VERSION 5.7 ;
  NOWIREEXTENSIONATPIN ON ;
  DIVIDERCHAR "/" ;
  BUSBITCHARS "[]" ;
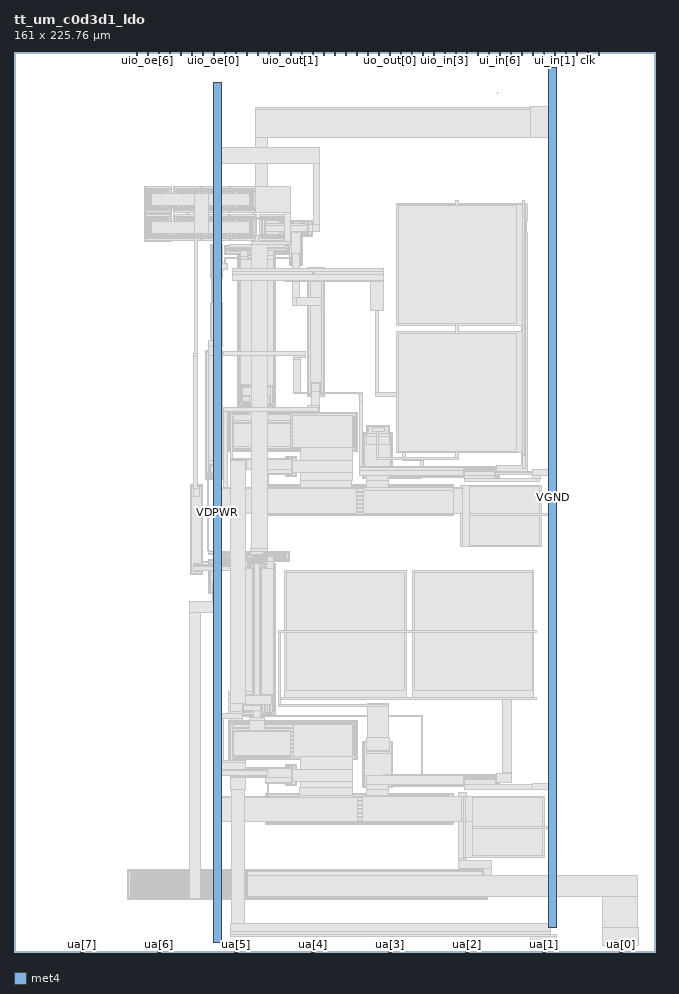
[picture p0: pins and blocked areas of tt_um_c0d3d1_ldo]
MACRO tt_um_c0d3d1_ldo
  CLASS BLOCK ;
  FOREIGN tt_um_c0d3d1_ldo ;
  ORIGIN 0.000 0.000 ;
  SIZE 161.000 BY 225.760 ;
  PIN clk
    DIRECTION INPUT ;
    USE SIGNAL ;
    PORT
      LAYER met4 ;
        RECT 143.830 224.760 144.130 225.760 ;
    END
  END clk
  PIN ena
    DIRECTION INPUT ;
    USE SIGNAL ;
    PORT
      LAYER met4 ;
        RECT 146.590 224.760 146.890 225.760 ;
    END
  END ena
  PIN rst_n
    DIRECTION INPUT ;
    USE SIGNAL ;
    PORT
      LAYER met4 ;
        RECT 141.070 224.760 141.370 225.760 ;
    END
  END rst_n
  PIN ua[0]
    DIRECTION INOUT ;
    USE SIGNAL ;
    ANTENNADIFFAREA 183.919998 ;
    PORT
      LAYER met4 ;
        RECT 151.810 0.000 152.710 1.000 ;
    END
  END ua[0]
  PIN ua[1]
    DIRECTION INOUT ;
    USE SIGNAL ;
    ANTENNAGATEAREA 738.719971 ;
    ANTENNADIFFAREA 1.740000 ;
    PORT
      LAYER met4 ;
        RECT 132.490 0.000 133.390 1.000 ;
    END
  END ua[1]
  PIN ua[2]
    DIRECTION INOUT ;
    USE SIGNAL ;
    PORT
      LAYER met4 ;
        RECT 113.170 0.000 114.070 1.000 ;
    END
  END ua[2]
  PIN ua[3]
    DIRECTION INOUT ;
    USE SIGNAL ;
    PORT
      LAYER met4 ;
        RECT 93.850 0.000 94.750 1.000 ;
    END
  END ua[3]
  PIN ua[4]
    DIRECTION INOUT ;
    USE SIGNAL ;
    PORT
      LAYER met4 ;
        RECT 74.530 0.000 75.430 1.000 ;
    END
  END ua[4]
  PIN ua[5]
    DIRECTION INOUT ;
    USE SIGNAL ;
    PORT
      LAYER met4 ;
        RECT 55.210 0.000 56.110 1.000 ;
    END
  END ua[5]
  PIN ua[6]
    DIRECTION INOUT ;
    USE SIGNAL ;
    PORT
      LAYER met4 ;
        RECT 35.890 0.000 36.790 1.000 ;
    END
  END ua[6]
  PIN ua[7]
    DIRECTION INOUT ;
    USE SIGNAL ;
    PORT
      LAYER met4 ;
        RECT 16.570 0.000 17.470 1.000 ;
    END
  END ua[7]
  PIN ui_in[0]
    DIRECTION INPUT ;
    USE SIGNAL ;
    PORT
      LAYER met4 ;
        RECT 138.310 224.760 138.610 225.760 ;
    END
  END ui_in[0]
  PIN ui_in[1]
    DIRECTION INPUT ;
    USE SIGNAL ;
    PORT
      LAYER met4 ;
        RECT 135.550 224.760 135.850 225.760 ;
    END
  END ui_in[1]
  PIN ui_in[2]
    DIRECTION INPUT ;
    USE SIGNAL ;
    PORT
      LAYER met4 ;
        RECT 132.790 224.760 133.090 225.760 ;
    END
  END ui_in[2]
  PIN ui_in[3]
    DIRECTION INPUT ;
    USE SIGNAL ;
    PORT
      LAYER met4 ;
        RECT 130.030 224.760 130.330 225.760 ;
    END
  END ui_in[3]
  PIN ui_in[4]
    DIRECTION INPUT ;
    USE SIGNAL ;
    PORT
      LAYER met4 ;
        RECT 127.270 224.760 127.570 225.760 ;
    END
  END ui_in[4]
  PIN ui_in[5]
    DIRECTION INPUT ;
    USE SIGNAL ;
    PORT
      LAYER met4 ;
        RECT 124.510 224.760 124.810 225.760 ;
    END
  END ui_in[5]
  PIN ui_in[6]
    DIRECTION INPUT ;
    USE SIGNAL ;
    PORT
      LAYER met4 ;
        RECT 121.750 224.760 122.050 225.760 ;
    END
  END ui_in[6]
  PIN ui_in[7]
    DIRECTION INPUT ;
    USE SIGNAL ;
    PORT
      LAYER met4 ;
        RECT 118.990 224.760 119.290 225.760 ;
    END
  END ui_in[7]
  PIN uio_in[0]
    DIRECTION INPUT ;
    USE SIGNAL ;
    PORT
      LAYER met4 ;
        RECT 116.230 224.760 116.530 225.760 ;
    END
  END uio_in[0]
  PIN uio_in[1]
    DIRECTION INPUT ;
    USE SIGNAL ;
    PORT
      LAYER met4 ;
        RECT 113.470 224.760 113.770 225.760 ;
    END
  END uio_in[1]
  PIN uio_in[2]
    DIRECTION INPUT ;
    USE SIGNAL ;
    PORT
      LAYER met4 ;
        RECT 110.710 224.760 111.010 225.760 ;
    END
  END uio_in[2]
  PIN uio_in[3]
    DIRECTION INPUT ;
    USE SIGNAL ;
    PORT
      LAYER met4 ;
        RECT 107.950 224.760 108.250 225.760 ;
    END
  END uio_in[3]
  PIN uio_in[4]
    DIRECTION INPUT ;
    USE SIGNAL ;
    PORT
      LAYER met4 ;
        RECT 105.190 224.760 105.490 225.760 ;
    END
  END uio_in[4]
  PIN uio_in[5]
    DIRECTION INPUT ;
    USE SIGNAL ;
    PORT
      LAYER met4 ;
        RECT 102.430 224.760 102.730 225.760 ;
    END
  END uio_in[5]
  PIN uio_in[6]
    DIRECTION INPUT ;
    USE SIGNAL ;
    PORT
      LAYER met4 ;
        RECT 99.670 224.760 99.970 225.760 ;
    END
  END uio_in[6]
  PIN uio_in[7]
    DIRECTION INPUT ;
    USE SIGNAL ;
    PORT
      LAYER met4 ;
        RECT 96.910 224.760 97.210 225.760 ;
    END
  END uio_in[7]
  PIN uio_oe[0]
    DIRECTION OUTPUT ;
    USE SIGNAL ;
    PORT
      LAYER met4 ;
        RECT 49.990 224.760 50.290 225.760 ;
    END
  END uio_oe[0]
  PIN uio_oe[1]
    DIRECTION OUTPUT ;
    USE SIGNAL ;
    PORT
      LAYER met4 ;
        RECT 47.230 224.760 47.530 225.760 ;
    END
  END uio_oe[1]
  PIN uio_oe[2]
    DIRECTION OUTPUT ;
    USE SIGNAL ;
    PORT
      LAYER met4 ;
        RECT 44.470 224.760 44.770 225.760 ;
    END
  END uio_oe[2]
  PIN uio_oe[3]
    DIRECTION OUTPUT ;
    USE SIGNAL ;
    PORT
      LAYER met4 ;
        RECT 41.710 224.760 42.010 225.760 ;
    END
  END uio_oe[3]
  PIN uio_oe[4]
    DIRECTION OUTPUT ;
    USE SIGNAL ;
    PORT
      LAYER met4 ;
        RECT 38.950 224.760 39.250 225.760 ;
    END
  END uio_oe[4]
  PIN uio_oe[5]
    DIRECTION OUTPUT ;
    USE SIGNAL ;
    PORT
      LAYER met4 ;
        RECT 36.190 224.760 36.490 225.760 ;
    END
  END uio_oe[5]
  PIN uio_oe[6]
    DIRECTION OUTPUT ;
    USE SIGNAL ;
    PORT
      LAYER met4 ;
        RECT 33.430 224.760 33.730 225.760 ;
    END
  END uio_oe[6]
  PIN uio_oe[7]
    DIRECTION OUTPUT ;
    USE SIGNAL ;
    PORT
      LAYER met4 ;
        RECT 30.670 224.760 30.970 225.760 ;
    END
  END uio_oe[7]
  PIN uio_out[0]
    DIRECTION OUTPUT ;
    USE SIGNAL ;
    PORT
      LAYER met4 ;
        RECT 72.070 224.760 72.370 225.760 ;
    END
  END uio_out[0]
  PIN uio_out[1]
    DIRECTION OUTPUT ;
    USE SIGNAL ;
    PORT
      LAYER met4 ;
        RECT 69.310 224.760 69.610 225.760 ;
    END
  END uio_out[1]
  PIN uio_out[2]
    DIRECTION OUTPUT ;
    USE SIGNAL ;
    PORT
      LAYER met4 ;
        RECT 66.550 224.760 66.850 225.760 ;
    END
  END uio_out[2]
  PIN uio_out[3]
    DIRECTION OUTPUT ;
    USE SIGNAL ;
    PORT
      LAYER met4 ;
        RECT 63.790 224.760 64.090 225.760 ;
    END
  END uio_out[3]
  PIN uio_out[4]
    DIRECTION OUTPUT ;
    USE SIGNAL ;
    PORT
      LAYER met4 ;
        RECT 61.030 224.760 61.330 225.760 ;
    END
  END uio_out[4]
  PIN uio_out[5]
    DIRECTION OUTPUT ;
    USE SIGNAL ;
    PORT
      LAYER met4 ;
        RECT 58.270 224.760 58.570 225.760 ;
    END
  END uio_out[5]
  PIN uio_out[6]
    DIRECTION OUTPUT ;
    USE SIGNAL ;
    PORT
      LAYER met4 ;
        RECT 55.510 224.760 55.810 225.760 ;
    END
  END uio_out[6]
  PIN uio_out[7]
    DIRECTION OUTPUT ;
    USE SIGNAL ;
    PORT
      LAYER met4 ;
        RECT 52.750 224.760 53.050 225.760 ;
    END
  END uio_out[7]
  PIN uo_out[0]
    DIRECTION OUTPUT ;
    USE SIGNAL ;
    PORT
      LAYER met4 ;
        RECT 94.150 224.760 94.450 225.760 ;
    END
  END uo_out[0]
  PIN uo_out[1]
    DIRECTION OUTPUT ;
    USE SIGNAL ;
    PORT
      LAYER met4 ;
        RECT 91.390 224.760 91.690 225.760 ;
    END
  END uo_out[1]
  PIN uo_out[2]
    DIRECTION OUTPUT ;
    USE SIGNAL ;
    PORT
      LAYER met4 ;
        RECT 88.630 224.760 88.930 225.760 ;
    END
  END uo_out[2]
  PIN uo_out[3]
    DIRECTION OUTPUT ;
    USE SIGNAL ;
    PORT
      LAYER met4 ;
        RECT 85.870 224.760 86.170 225.760 ;
    END
  END uo_out[3]
  PIN uo_out[4]
    DIRECTION OUTPUT ;
    USE SIGNAL ;
    PORT
      LAYER met4 ;
        RECT 83.110 224.760 83.410 225.760 ;
    END
  END uo_out[4]
  PIN uo_out[5]
    DIRECTION OUTPUT ;
    USE SIGNAL ;
    PORT
      LAYER met4 ;
        RECT 80.350 224.760 80.650 225.760 ;
    END
  END uo_out[5]
  PIN uo_out[6]
    DIRECTION OUTPUT ;
    USE SIGNAL ;
    PORT
      LAYER met4 ;
        RECT 77.590 224.760 77.890 225.760 ;
    END
  END uo_out[6]
  PIN uo_out[7]
    DIRECTION OUTPUT ;
    USE SIGNAL ;
    PORT
      LAYER met4 ;
        RECT 74.830 224.760 75.130 225.760 ;
    END
  END uo_out[7]
  PIN VDPWR
    DIRECTION INOUT ;
    USE POWER ;
    PORT
      LAYER met4 ;
        RECT 50.120 2.420 52.120 218.180 ;
    END
  END VDPWR
  PIN VGND
    DIRECTION INOUT ;
    USE GROUND ;
    PORT
      LAYER met4 ;
        RECT 134.120 6.130 136.120 221.890 ;
    END
  END VGND
  OBS
      LAYER pwell ;
        RECT 121.160 215.360 121.200 215.600 ;
        RECT 135.160 215.360 135.200 215.600 ;
        RECT 32.735 191.265 39.435 192.030 ;
        RECT 32.735 186.095 33.500 191.265 ;
        RECT 38.670 186.095 39.435 191.265 ;
        RECT 32.735 185.330 39.435 186.095 ;
        RECT 40.125 191.325 46.825 192.090 ;
        RECT 40.125 186.155 40.890 191.325 ;
        RECT 46.060 186.155 46.825 191.325 ;
        RECT 40.125 185.390 46.825 186.155 ;
        RECT 47.125 191.325 53.825 192.090 ;
        RECT 47.125 186.155 47.890 191.325 ;
        RECT 53.060 186.155 53.825 191.325 ;
        RECT 47.125 185.390 53.825 186.155 ;
        RECT 54.125 191.325 60.825 192.090 ;
        RECT 54.125 186.155 54.890 191.325 ;
        RECT 60.060 186.155 60.825 191.325 ;
        RECT 54.125 185.390 60.825 186.155 ;
        RECT 32.735 184.265 39.435 185.030 ;
        RECT 32.735 179.095 33.500 184.265 ;
        RECT 38.670 179.095 39.435 184.265 ;
        RECT 32.735 178.330 39.435 179.095 ;
        RECT 40.125 184.325 46.825 185.090 ;
        RECT 40.125 179.155 40.890 184.325 ;
        RECT 46.060 179.155 46.825 184.325 ;
        RECT 40.125 178.390 46.825 179.155 ;
        RECT 47.125 184.325 53.825 185.090 ;
        RECT 47.125 179.155 47.890 184.325 ;
        RECT 53.060 179.155 53.825 184.325 ;
        RECT 47.125 178.390 53.825 179.155 ;
        RECT 54.125 184.325 60.825 185.090 ;
        RECT 54.125 179.155 54.890 184.325 ;
        RECT 60.060 179.155 60.825 184.325 ;
        RECT 54.125 178.390 60.825 179.155 ;
        RECT 61.490 184.335 68.190 185.100 ;
        RECT 61.490 179.165 62.255 184.335 ;
        RECT 67.425 179.165 68.190 184.335 ;
        RECT 61.490 178.400 68.190 179.165 ;
        RECT 49.340 169.310 52.410 177.580 ;
        RECT 52.920 174.970 61.020 177.290 ;
        RECT 61.060 175.010 69.160 177.330 ;
      LAYER nwell ;
        RECT 56.170 174.910 60.440 174.940 ;
        RECT 56.170 174.870 61.720 174.910 ;
      LAYER pwell ;
        RECT 49.280 152.000 52.350 162.940 ;
      LAYER nwell ;
        RECT 48.030 118.640 52.300 150.830 ;
        RECT 56.170 136.750 65.695 174.870 ;
      LAYER pwell ;
        RECT 69.230 172.120 72.300 183.540 ;
      LAYER nwell ;
        RECT 72.615 179.585 74.935 183.575 ;
        RECT 73.600 139.430 77.870 171.620 ;
        RECT 60.170 136.690 65.695 136.750 ;
        RECT 61.425 136.680 65.695 136.690 ;
        RECT 53.880 125.650 86.070 135.400 ;
        RECT 68.170 119.160 70.850 124.350 ;
      LAYER pwell ;
        RECT 87.520 118.670 94.910 130.220 ;
        RECT 101.770 118.920 121.870 121.890 ;
        RECT 44.270 94.580 47.340 117.150 ;
      LAYER nwell ;
        RECT 63.010 109.450 110.200 117.180 ;
      LAYER pwell ;
        RECT 48.900 98.450 51.970 98.470 ;
        RECT 48.860 90.000 51.970 98.450 ;
        RECT 52.650 98.060 60.750 100.380 ;
        RECT 61.000 98.080 69.100 100.400 ;
      LAYER nwell ;
        RECT 56.190 97.520 60.460 97.530 ;
        RECT 56.190 97.460 61.640 97.520 ;
      LAYER pwell ;
        RECT 48.860 89.980 51.930 90.000 ;
      LAYER nwell ;
        RECT 56.190 59.340 65.715 97.460 ;
        RECT 59.160 59.290 65.715 59.340 ;
        RECT 61.445 59.270 65.715 59.290 ;
        RECT 59.160 57.990 63.230 58.000 ;
        RECT 53.900 48.240 86.090 57.990 ;
        RECT 68.190 41.750 70.870 46.940 ;
      LAYER pwell ;
        RECT 87.540 41.260 94.930 52.810 ;
        RECT 101.790 41.510 121.890 44.480 ;
      LAYER nwell ;
        RECT 63.030 32.040 110.220 39.770 ;
        RECT 28.485 13.205 118.675 20.635 ;
      LAYER li1 ;
        RECT 60.600 191.960 63.530 191.970 ;
        RECT 32.865 191.405 39.305 191.900 ;
        RECT 32.865 185.955 33.360 191.405 ;
        RECT 33.680 190.725 38.490 191.085 ;
        RECT 33.680 186.635 34.040 190.725 ;
        RECT 34.350 186.945 37.820 190.415 ;
        RECT 38.130 186.900 38.490 190.725 ;
        RECT 38.810 186.900 39.305 191.405 ;
        RECT 38.130 186.890 39.305 186.900 ;
        RECT 40.255 191.465 46.695 191.960 ;
        RECT 40.255 191.065 40.750 191.465 ;
        RECT 41.070 191.065 45.880 191.145 ;
        RECT 46.200 191.065 46.695 191.465 ;
        RECT 47.255 191.465 53.695 191.960 ;
        RECT 47.255 191.065 47.750 191.465 ;
        RECT 48.070 191.065 52.880 191.145 ;
        RECT 53.200 191.065 53.695 191.465 ;
        RECT 54.255 191.465 63.530 191.960 ;
        RECT 54.255 191.065 54.750 191.465 ;
        RECT 55.070 191.065 59.880 191.145 ;
        RECT 60.200 191.065 63.530 191.465 ;
        RECT 40.255 190.785 63.530 191.065 ;
        RECT 40.255 186.890 40.750 190.785 ;
        RECT 38.130 186.695 40.750 186.890 ;
        RECT 41.070 186.695 41.430 190.785 ;
        RECT 41.740 187.005 45.210 190.475 ;
        RECT 45.520 186.695 45.880 190.785 ;
        RECT 46.200 186.695 46.695 190.785 ;
        RECT 47.255 186.695 47.750 190.785 ;
        RECT 48.070 186.695 48.430 190.785 ;
        RECT 48.740 187.005 52.210 190.475 ;
        RECT 52.520 186.695 52.880 190.785 ;
        RECT 53.200 186.695 53.695 190.785 ;
        RECT 54.255 186.695 54.750 190.785 ;
        RECT 55.070 186.695 55.430 190.785 ;
        RECT 55.740 187.005 59.210 190.475 ;
        RECT 59.520 186.695 59.880 190.785 ;
        RECT 60.200 186.695 63.530 190.785 ;
        RECT 38.130 186.635 63.530 186.695 ;
        RECT 33.680 186.450 63.530 186.635 ;
        RECT 33.680 186.430 39.305 186.450 ;
        RECT 33.680 186.275 38.490 186.430 ;
        RECT 38.810 185.955 39.305 186.430 ;
        RECT 32.865 185.460 39.305 185.955 ;
        RECT 40.255 186.335 63.530 186.450 ;
        RECT 40.255 186.015 40.750 186.335 ;
        RECT 46.200 186.015 46.695 186.335 ;
        RECT 40.255 185.520 46.695 186.015 ;
        RECT 47.255 186.015 47.750 186.335 ;
        RECT 53.200 186.015 53.695 186.335 ;
        RECT 47.255 185.520 53.695 186.015 ;
        RECT 54.255 186.015 54.750 186.335 ;
        RECT 60.200 186.015 63.530 186.335 ;
        RECT 54.255 185.550 63.530 186.015 ;
        RECT 54.255 185.520 60.695 185.550 ;
        RECT 33.440 184.900 33.985 185.460 ;
        RECT 43.345 184.960 43.840 185.520 ;
        RECT 50.345 184.960 50.830 185.520 ;
        RECT 59.920 184.960 60.355 185.520 ;
        RECT 32.865 184.405 39.305 184.900 ;
        RECT 32.865 178.955 33.360 184.405 ;
        RECT 33.680 183.725 38.490 184.085 ;
        RECT 33.680 179.635 34.040 183.725 ;
        RECT 34.350 179.945 37.820 183.415 ;
        RECT 38.130 179.750 38.490 183.725 ;
        RECT 38.810 179.750 39.305 184.405 ;
        RECT 38.130 179.710 39.305 179.750 ;
        RECT 40.255 184.465 46.695 184.960 ;
        RECT 40.255 184.115 40.750 184.465 ;
        RECT 41.070 184.120 45.880 184.145 ;
        RECT 46.200 184.120 46.695 184.465 ;
        RECT 47.255 184.465 53.695 184.960 ;
        RECT 47.255 184.120 47.750 184.465 ;
        RECT 48.070 184.120 52.880 184.145 ;
        RECT 53.200 184.120 53.695 184.465 ;
        RECT 54.255 184.465 60.695 184.960 ;
        RECT 54.255 184.120 54.750 184.465 ;
        RECT 55.070 184.120 59.880 184.145 ;
        RECT 60.200 184.120 60.695 184.465 ;
        RECT 61.620 184.475 68.060 184.970 ;
        RECT 61.620 184.120 62.115 184.475 ;
        RECT 62.435 184.120 67.245 184.155 ;
        RECT 41.070 184.115 67.245 184.120 ;
        RECT 40.255 183.845 67.245 184.115 ;
        RECT 40.255 183.275 40.760 183.845 ;
        RECT 41.070 183.840 67.245 183.845 ;
        RECT 41.070 183.785 45.880 183.840 ;
        RECT 40.255 180.205 40.750 183.275 ;
        RECT 40.255 179.770 40.760 180.205 ;
        RECT 41.070 179.770 41.430 183.785 ;
        RECT 41.740 180.005 45.210 183.475 ;
        RECT 45.520 179.770 45.880 183.785 ;
        RECT 46.200 179.770 46.695 183.840 ;
        RECT 47.255 179.770 47.750 183.840 ;
        RECT 48.070 183.785 52.880 183.840 ;
        RECT 48.070 179.770 48.430 183.785 ;
        RECT 48.740 180.005 52.210 183.475 ;
        RECT 52.520 179.770 52.880 183.785 ;
        RECT 53.200 179.770 53.695 183.840 ;
        RECT 54.255 179.770 54.750 183.840 ;
        RECT 55.070 183.785 59.880 183.840 ;
        RECT 55.070 179.770 55.430 183.785 ;
        RECT 55.740 180.005 59.210 183.475 ;
        RECT 59.520 179.770 59.880 183.785 ;
        RECT 60.200 179.770 60.695 183.840 ;
        RECT 61.620 179.980 62.115 183.840 ;
        RECT 62.435 183.795 67.245 183.840 ;
        RECT 62.435 179.980 62.795 183.795 ;
        RECT 63.105 180.015 66.575 183.485 ;
        RECT 66.885 183.370 67.245 183.795 ;
        RECT 67.565 183.370 68.060 184.475 ;
        RECT 66.885 183.360 70.220 183.370 ;
        RECT 66.885 183.190 72.120 183.360 ;
        RECT 66.885 183.020 70.220 183.190 ;
        RECT 61.620 179.770 62.795 179.980 ;
        RECT 40.255 179.710 62.795 179.770 ;
        RECT 38.130 179.705 62.795 179.710 ;
        RECT 66.885 179.705 67.245 183.020 ;
        RECT 38.130 179.635 67.245 179.705 ;
        RECT 33.680 179.410 67.245 179.635 ;
        RECT 33.680 179.320 40.750 179.410 ;
        RECT 41.070 179.335 45.880 179.410 ;
        RECT 33.680 179.275 38.490 179.320 ;
        RECT 38.810 179.270 40.750 179.320 ;
        RECT 38.810 179.030 39.305 179.270 ;
        RECT 40.255 179.030 40.750 179.270 ;
        RECT 38.810 179.015 40.750 179.030 ;
        RECT 46.200 179.015 46.695 179.410 ;
        RECT 38.810 178.955 46.695 179.015 ;
        RECT 32.865 178.570 46.695 178.955 ;
        RECT 32.865 178.460 39.305 178.570 ;
        RECT 40.255 178.520 46.695 178.570 ;
        RECT 47.255 179.015 47.750 179.410 ;
        RECT 48.070 179.335 52.880 179.410 ;
        RECT 53.200 179.015 53.695 179.410 ;
        RECT 47.255 178.520 53.695 179.015 ;
        RECT 54.255 179.015 54.750 179.410 ;
        RECT 55.070 179.335 59.880 179.410 ;
        RECT 60.200 179.025 62.115 179.410 ;
        RECT 62.435 179.345 67.245 179.410 ;
        RECT 67.565 179.025 68.060 183.020 ;
        RECT 60.200 179.015 68.060 179.025 ;
        RECT 54.255 178.530 68.060 179.015 ;
        RECT 54.255 178.520 61.830 178.530 ;
        RECT 45.160 177.950 45.980 178.520 ;
        RECT 49.960 177.400 51.800 178.520 ;
        RECT 60.470 178.460 61.830 178.520 ;
        RECT 60.470 178.440 61.470 178.460 ;
        RECT 49.520 177.230 52.230 177.400 ;
        RECT 49.520 170.070 49.690 177.230 ;
        RECT 50.170 174.590 51.580 176.750 ;
        RECT 50.170 170.140 51.580 172.300 ;
        RECT 49.450 169.660 49.790 170.070 ;
        RECT 52.060 169.660 52.230 177.230 ;
        RECT 53.100 176.940 60.840 177.110 ;
        RECT 53.100 175.320 53.270 176.940 ;
        RECT 55.470 176.540 58.440 176.940 ;
        RECT 53.950 176.370 59.990 176.540 ;
        RECT 53.610 175.950 53.780 176.310 ;
        RECT 60.160 175.950 60.330 176.310 ;
        RECT 53.950 175.720 59.990 175.890 ;
        RECT 60.670 175.320 60.840 176.940 ;
        RECT 53.100 175.150 60.840 175.320 ;
        RECT 61.240 176.980 68.980 177.150 ;
        RECT 61.240 175.360 61.410 176.980 ;
        RECT 63.580 176.580 66.550 176.980 ;
        RECT 62.090 176.410 68.130 176.580 ;
        RECT 61.750 175.990 61.920 176.350 ;
        RECT 68.300 175.990 68.470 176.350 ;
        RECT 62.090 175.760 68.130 175.930 ;
        RECT 68.810 175.360 68.980 176.980 ;
        RECT 61.240 175.190 68.980 175.360 ;
        RECT 49.450 169.490 52.230 169.660 ;
        RECT 56.350 174.590 60.260 174.760 ;
        RECT 49.450 162.760 49.790 169.490 ;
        RECT 49.450 162.600 52.170 162.760 ;
        RECT 49.460 162.590 52.170 162.600 ;
        RECT 49.460 152.350 49.630 162.590 ;
        RECT 50.110 159.950 51.520 162.110 ;
        RECT 50.110 152.830 51.520 154.990 ;
        RECT 52.000 152.350 52.170 162.590 ;
        RECT 49.460 152.180 52.170 152.350 ;
        RECT 48.210 150.480 52.120 150.650 ;
        RECT 48.210 118.990 48.380 150.480 ;
        RECT 49.010 149.970 49.370 150.140 ;
        RECT 49.660 149.970 50.020 150.140 ;
        RECT 50.310 149.970 50.670 150.140 ;
        RECT 50.960 149.970 51.320 150.140 ;
        RECT 48.780 119.715 48.950 149.755 ;
        RECT 49.430 119.715 49.600 149.755 ;
        RECT 50.080 119.715 50.250 149.755 ;
        RECT 50.730 119.715 50.900 149.755 ;
        RECT 51.380 119.715 51.550 149.755 ;
        RECT 49.010 119.330 49.370 119.500 ;
        RECT 49.660 119.330 50.020 119.500 ;
        RECT 50.310 119.330 50.670 119.500 ;
        RECT 50.960 119.330 51.320 119.500 ;
        RECT 50.580 118.990 51.580 119.010 ;
        RECT 51.950 118.990 52.120 150.480 ;
        RECT 56.350 137.100 56.520 174.590 ;
        RECT 57.150 174.080 57.510 174.250 ;
        RECT 57.800 174.080 58.160 174.250 ;
        RECT 58.450 174.080 58.810 174.250 ;
        RECT 59.100 174.080 59.460 174.250 ;
        RECT 56.920 137.825 57.090 173.865 ;
        RECT 57.570 137.825 57.740 173.865 ;
        RECT 58.220 137.825 58.390 173.865 ;
        RECT 58.870 137.825 59.040 173.865 ;
        RECT 59.520 137.825 59.690 173.865 ;
        RECT 60.090 138.280 60.260 174.590 ;
        RECT 61.605 174.520 65.515 174.690 ;
        RECT 61.605 138.280 61.775 174.520 ;
        RECT 62.405 174.010 62.765 174.180 ;
        RECT 63.055 174.010 63.415 174.180 ;
        RECT 63.705 174.010 64.065 174.180 ;
        RECT 64.355 174.010 64.715 174.180 ;
        RECT 57.365 137.610 59.185 137.640 ;
        RECT 57.150 137.440 59.460 137.610 ;
        RECT 60.090 137.490 61.780 138.280 ;
        RECT 62.175 137.755 62.345 173.795 ;
        RECT 62.825 137.755 62.995 173.795 ;
        RECT 63.475 137.755 63.645 173.795 ;
        RECT 64.125 137.755 64.295 173.795 ;
        RECT 64.775 137.755 64.945 173.795 ;
        RECT 60.090 137.100 60.260 137.490 ;
        RECT 56.350 136.930 60.260 137.100 ;
        RECT 61.605 137.030 61.775 137.490 ;
        RECT 62.405 137.370 62.765 137.540 ;
        RECT 63.055 137.370 63.415 137.540 ;
        RECT 63.705 137.370 64.065 137.540 ;
        RECT 64.355 137.370 64.715 137.540 ;
        RECT 65.345 137.030 65.515 174.520 ;
        RECT 69.410 172.470 69.580 183.020 ;
        RECT 70.060 180.550 71.470 182.710 ;
        RECT 70.060 172.950 71.470 175.110 ;
        RECT 71.950 172.470 72.120 183.190 ;
        RECT 72.795 183.225 74.755 183.395 ;
        RECT 72.795 179.935 72.965 183.225 ;
        RECT 73.595 182.715 73.955 182.885 ;
        RECT 73.365 180.660 73.535 182.500 ;
        RECT 74.015 182.260 74.185 182.500 ;
        RECT 74.585 182.260 74.755 183.225 ;
        RECT 74.015 180.840 74.755 182.260 ;
        RECT 74.015 180.660 74.185 180.840 ;
        RECT 73.595 180.275 73.955 180.445 ;
        RECT 74.585 179.935 74.755 180.840 ;
        RECT 72.795 179.765 74.755 179.935 ;
        RECT 69.410 172.300 72.120 172.470 ;
        RECT 73.780 171.270 77.690 171.440 ;
        RECT 73.780 139.780 73.950 171.270 ;
        RECT 74.580 170.760 74.940 170.930 ;
        RECT 75.230 170.760 75.590 170.930 ;
        RECT 75.880 170.760 76.240 170.930 ;
        RECT 76.530 170.760 76.890 170.930 ;
        RECT 74.350 140.505 74.520 170.545 ;
        RECT 75.000 140.505 75.170 170.545 ;
        RECT 75.650 140.505 75.820 170.545 ;
        RECT 76.300 140.505 76.470 170.545 ;
        RECT 76.950 140.505 77.120 170.545 ;
        RECT 74.580 140.120 74.940 140.290 ;
        RECT 75.230 140.120 75.590 140.290 ;
        RECT 75.880 140.120 76.240 140.290 ;
        RECT 76.530 140.120 76.890 140.290 ;
        RECT 77.520 139.810 77.690 171.270 ;
        RECT 77.220 139.780 77.700 139.810 ;
        RECT 73.780 139.610 77.700 139.780 ;
        RECT 77.220 139.270 77.700 139.610 ;
        RECT 61.605 136.860 65.515 137.030 ;
        RECT 54.060 135.050 85.890 135.220 ;
        RECT 54.060 126.000 54.230 135.050 ;
        RECT 54.955 134.480 84.995 134.650 ;
        RECT 54.570 133.700 54.740 134.420 ;
        RECT 85.210 133.700 85.380 134.420 ;
        RECT 54.955 133.470 84.995 133.640 ;
        RECT 54.570 132.690 54.740 133.410 ;
        RECT 85.210 132.690 85.380 133.410 ;
        RECT 54.955 132.460 84.995 132.630 ;
        RECT 54.570 131.680 54.740 132.400 ;
        RECT 85.210 131.680 85.380 132.400 ;
        RECT 54.955 131.450 84.995 131.620 ;
        RECT 54.570 130.670 54.740 131.390 ;
        RECT 85.210 130.670 85.380 131.390 ;
        RECT 54.955 130.440 84.995 130.610 ;
        RECT 54.570 129.660 54.740 130.380 ;
        RECT 85.210 129.660 85.380 130.380 ;
        RECT 54.955 129.430 84.995 129.600 ;
        RECT 54.570 128.650 54.740 129.370 ;
        RECT 85.210 128.650 85.380 129.370 ;
        RECT 54.955 128.420 84.995 128.590 ;
        RECT 54.570 127.640 54.740 128.360 ;
        RECT 85.210 127.640 85.380 128.360 ;
        RECT 54.955 127.410 84.995 127.580 ;
        RECT 54.570 126.630 54.740 127.350 ;
        RECT 85.210 126.630 85.380 127.350 ;
        RECT 54.955 126.400 84.995 126.570 ;
        RECT 85.720 126.000 85.890 135.050 ;
        RECT 54.060 125.830 85.890 126.000 ;
        RECT 87.700 129.870 94.730 130.040 ;
        RECT 71.810 125.580 84.800 125.830 ;
        RECT 68.350 124.000 70.670 124.170 ;
        RECT 68.350 119.510 68.520 124.000 ;
        RECT 69.150 123.490 69.870 123.660 ;
        RECT 68.920 120.235 69.090 123.275 ;
        RECT 69.930 123.240 70.100 123.275 ;
        RECT 70.500 123.240 70.670 124.000 ;
        RECT 69.930 120.410 70.670 123.240 ;
        RECT 69.930 120.235 70.100 120.410 ;
        RECT 69.150 119.850 69.870 120.020 ;
        RECT 70.500 119.510 70.670 120.410 ;
        RECT 68.350 119.340 70.670 119.510 ;
        RECT 48.210 118.820 52.120 118.990 ;
        RECT 87.700 119.020 87.870 129.870 ;
        RECT 88.350 127.230 94.080 129.390 ;
        RECT 88.350 119.500 94.080 121.660 ;
        RECT 94.560 119.260 94.730 129.870 ;
        RECT 101.950 121.540 121.690 121.710 ;
        RECT 101.950 119.270 102.120 121.540 ;
        RECT 102.800 120.970 120.840 121.140 ;
        RECT 102.460 120.550 102.630 120.910 ;
        RECT 121.010 120.550 121.180 120.910 ;
        RECT 102.800 120.320 120.840 120.490 ;
        RECT 102.460 119.900 102.630 120.260 ;
        RECT 121.010 119.900 121.180 120.260 ;
        RECT 102.800 119.670 120.840 119.840 ;
        RECT 113.100 119.270 120.580 119.340 ;
        RECT 121.520 119.270 121.690 121.540 ;
        RECT 101.950 119.260 121.690 119.270 ;
        RECT 94.540 119.100 121.690 119.260 ;
        RECT 94.540 119.020 102.250 119.100 ;
        RECT 87.700 118.870 102.250 119.020 ;
        RECT 87.700 118.850 94.730 118.870 ;
        RECT 113.100 118.850 120.580 119.100 ;
        RECT 50.580 118.390 51.580 118.820 ;
        RECT 71.840 117.000 84.680 117.280 ;
        RECT 44.450 116.800 47.160 116.970 ;
        RECT 44.450 94.930 44.620 116.800 ;
        RECT 45.200 116.320 46.500 116.800 ;
        RECT 45.100 114.160 46.510 116.320 ;
        RECT 46.990 97.850 47.160 116.800 ;
        RECT 63.190 116.830 110.020 117.000 ;
        RECT 63.190 109.800 63.360 116.830 ;
        RECT 64.085 116.260 109.125 116.430 ;
        RECT 63.700 115.480 63.870 116.200 ;
        RECT 109.340 115.480 109.510 116.200 ;
        RECT 64.085 115.250 109.125 115.420 ;
        RECT 63.700 114.470 63.870 115.190 ;
        RECT 109.340 114.470 109.510 115.190 ;
        RECT 64.085 114.240 109.125 114.410 ;
        RECT 63.700 113.460 63.870 114.180 ;
        RECT 109.340 113.460 109.510 114.180 ;
        RECT 64.085 113.230 109.125 113.400 ;
        RECT 63.700 112.450 63.870 113.170 ;
        RECT 109.340 112.450 109.510 113.170 ;
        RECT 64.085 112.220 109.125 112.390 ;
        RECT 63.700 111.440 63.870 112.160 ;
        RECT 109.340 111.440 109.510 112.160 ;
        RECT 64.085 111.210 109.125 111.380 ;
        RECT 63.700 110.430 63.870 111.150 ;
        RECT 109.340 110.430 109.510 111.150 ;
        RECT 64.085 110.200 109.125 110.370 ;
        RECT 109.850 109.800 110.020 116.830 ;
        RECT 63.190 109.630 110.020 109.800 ;
        RECT 52.830 100.030 60.570 100.200 ;
        RECT 52.830 98.410 53.000 100.030 ;
        RECT 56.290 99.630 56.730 100.030 ;
        RECT 53.680 99.460 59.720 99.630 ;
        RECT 56.290 99.430 56.730 99.460 ;
        RECT 53.340 99.040 53.510 99.400 ;
        RECT 59.890 99.040 60.060 99.400 ;
        RECT 53.680 98.810 59.720 98.980 ;
        RECT 60.400 98.410 60.570 100.030 ;
        RECT 49.080 98.120 51.790 98.290 ;
        RECT 52.830 98.240 60.570 98.410 ;
        RECT 61.180 100.050 68.920 100.220 ;
        RECT 61.180 98.430 61.350 100.050 ;
        RECT 64.540 99.650 64.980 100.050 ;
        RECT 62.030 99.480 68.070 99.650 ;
        RECT 61.690 99.060 61.860 99.420 ;
        RECT 68.240 99.060 68.410 99.420 ;
        RECT 62.030 98.830 68.070 99.000 ;
        RECT 68.750 98.430 68.920 100.050 ;
        RECT 61.180 98.260 68.920 98.430 ;
        RECT 49.080 97.850 49.250 98.120 ;
        RECT 46.990 97.600 49.280 97.850 ;
        RECT 45.100 95.410 46.510 97.570 ;
        RECT 46.990 94.930 47.160 97.600 ;
        RECT 44.450 94.760 47.160 94.930 ;
        RECT 49.080 90.350 49.250 97.600 ;
        RECT 49.730 95.480 51.140 97.640 ;
        RECT 49.730 90.830 51.140 92.990 ;
        RECT 51.620 90.350 51.790 98.120 ;
        RECT 49.080 90.180 51.790 90.350 ;
        RECT 56.370 97.180 60.280 97.350 ;
        RECT 56.370 59.690 56.540 97.180 ;
        RECT 57.170 96.670 57.530 96.840 ;
        RECT 57.820 96.670 58.180 96.840 ;
        RECT 58.470 96.670 58.830 96.840 ;
        RECT 59.120 96.670 59.480 96.840 ;
        RECT 56.940 60.415 57.110 96.455 ;
        RECT 57.590 60.415 57.760 96.455 ;
        RECT 58.240 60.415 58.410 96.455 ;
        RECT 58.890 60.415 59.060 96.455 ;
        RECT 59.540 60.415 59.710 96.455 ;
        RECT 60.110 61.440 60.280 97.180 ;
        RECT 61.625 97.110 65.535 97.280 ;
        RECT 61.625 61.440 61.795 97.110 ;
        RECT 62.425 96.600 62.785 96.770 ;
        RECT 63.075 96.600 63.435 96.770 ;
        RECT 63.725 96.600 64.085 96.770 ;
        RECT 64.375 96.600 64.735 96.770 ;
        RECT 60.110 60.450 61.795 61.440 ;
        RECT 57.385 60.200 59.205 60.230 ;
        RECT 57.170 60.030 59.480 60.200 ;
        RECT 60.110 59.690 60.280 60.450 ;
        RECT 56.370 59.520 60.280 59.690 ;
        RECT 61.625 59.620 61.795 60.450 ;
        RECT 62.195 60.345 62.365 96.385 ;
        RECT 62.845 60.345 63.015 96.385 ;
        RECT 63.495 60.345 63.665 96.385 ;
        RECT 64.145 60.345 64.315 96.385 ;
        RECT 64.795 60.345 64.965 96.385 ;
        RECT 62.425 59.960 62.785 60.130 ;
        RECT 63.075 59.960 63.435 60.130 ;
        RECT 63.725 59.960 64.085 60.130 ;
        RECT 64.375 59.960 64.735 60.130 ;
        RECT 65.365 59.620 65.535 97.110 ;
        RECT 61.625 59.450 65.535 59.620 ;
        RECT 54.080 57.640 85.910 57.810 ;
        RECT 54.080 48.590 54.250 57.640 ;
        RECT 54.975 57.070 85.015 57.240 ;
        RECT 54.590 56.290 54.760 57.010 ;
        RECT 85.230 56.290 85.400 57.010 ;
        RECT 54.975 56.060 85.015 56.230 ;
        RECT 54.590 55.280 54.760 56.000 ;
        RECT 85.230 55.280 85.400 56.000 ;
        RECT 54.975 55.050 85.015 55.220 ;
        RECT 54.590 54.270 54.760 54.990 ;
        RECT 85.230 54.270 85.400 54.990 ;
        RECT 54.975 54.040 85.015 54.210 ;
        RECT 54.590 53.260 54.760 53.980 ;
        RECT 85.230 53.260 85.400 53.980 ;
        RECT 54.975 53.030 85.015 53.200 ;
        RECT 54.590 52.250 54.760 52.970 ;
        RECT 85.230 52.250 85.400 52.970 ;
        RECT 54.975 52.020 85.015 52.190 ;
        RECT 54.590 51.240 54.760 51.960 ;
        RECT 85.230 51.240 85.400 51.960 ;
        RECT 54.975 51.010 85.015 51.180 ;
        RECT 54.590 50.230 54.760 50.950 ;
        RECT 85.230 50.230 85.400 50.950 ;
        RECT 54.975 50.000 85.015 50.170 ;
        RECT 54.590 49.220 54.760 49.940 ;
        RECT 85.230 49.220 85.400 49.940 ;
        RECT 54.975 48.990 85.015 49.160 ;
        RECT 85.740 48.590 85.910 57.640 ;
        RECT 54.080 48.420 85.910 48.590 ;
        RECT 87.720 52.460 94.750 52.630 ;
        RECT 71.810 48.010 84.810 48.420 ;
        RECT 68.370 46.590 70.690 46.760 ;
        RECT 68.370 42.100 68.540 46.590 ;
        RECT 69.170 46.080 69.890 46.250 ;
        RECT 68.940 42.825 69.110 45.865 ;
        RECT 69.950 45.830 70.120 45.865 ;
        RECT 70.520 45.830 70.690 46.590 ;
        RECT 69.950 43.000 70.690 45.830 ;
        RECT 69.950 42.825 70.120 43.000 ;
        RECT 69.170 42.440 69.890 42.610 ;
        RECT 70.520 42.100 70.690 43.000 ;
        RECT 68.370 41.930 70.690 42.100 ;
        RECT 87.720 41.610 87.890 52.460 ;
        RECT 88.370 49.820 94.100 51.980 ;
        RECT 88.370 42.090 94.100 44.250 ;
        RECT 94.580 41.860 94.750 52.460 ;
        RECT 101.970 44.130 121.710 44.300 ;
        RECT 101.970 41.860 102.140 44.130 ;
        RECT 102.820 43.560 120.860 43.730 ;
        RECT 102.480 43.140 102.650 43.500 ;
        RECT 121.030 43.140 121.200 43.500 ;
        RECT 102.820 42.910 120.860 43.080 ;
        RECT 102.480 42.490 102.650 42.850 ;
        RECT 121.030 42.490 121.200 42.850 ;
        RECT 102.820 42.260 120.860 42.430 ;
        RECT 113.160 41.860 120.910 41.890 ;
        RECT 121.540 41.860 121.710 44.130 ;
        RECT 94.580 41.690 121.710 41.860 ;
        RECT 94.580 41.610 102.400 41.690 ;
        RECT 87.720 41.470 102.400 41.610 ;
        RECT 87.720 41.440 94.750 41.470 ;
        RECT 113.160 41.440 120.910 41.690 ;
        RECT 71.830 39.590 84.790 39.920 ;
        RECT 63.210 39.420 110.040 39.590 ;
        RECT 63.210 32.390 63.380 39.420 ;
        RECT 71.830 39.410 84.790 39.420 ;
        RECT 71.860 39.390 84.660 39.410 ;
        RECT 64.105 38.850 109.145 39.020 ;
        RECT 63.720 38.070 63.890 38.790 ;
        RECT 109.360 38.070 109.530 38.790 ;
        RECT 64.105 37.840 109.145 38.010 ;
        RECT 63.720 37.060 63.890 37.780 ;
        RECT 109.360 37.060 109.530 37.780 ;
        RECT 64.105 36.830 109.145 37.000 ;
        RECT 63.720 36.050 63.890 36.770 ;
        RECT 109.360 36.050 109.530 36.770 ;
        RECT 64.105 35.820 109.145 35.990 ;
        RECT 63.720 35.040 63.890 35.760 ;
        RECT 109.360 35.040 109.530 35.760 ;
        RECT 64.105 34.810 109.145 34.980 ;
        RECT 63.720 34.030 63.890 34.750 ;
        RECT 109.360 34.030 109.530 34.750 ;
        RECT 64.105 33.800 109.145 33.970 ;
        RECT 63.720 33.020 63.890 33.740 ;
        RECT 109.360 33.020 109.530 33.740 ;
        RECT 64.105 32.790 109.145 32.960 ;
        RECT 109.870 32.390 110.040 39.420 ;
        RECT 63.210 32.220 110.040 32.390 ;
        RECT 50.100 20.455 52.100 20.600 ;
        RECT 28.665 20.285 118.495 20.455 ;
        RECT 28.665 13.555 28.835 20.285 ;
        RECT 50.100 20.180 52.100 20.285 ;
        RECT 29.175 14.040 29.345 19.800 ;
        RECT 29.560 19.715 117.600 19.885 ;
        RECT 29.560 19.235 117.600 19.405 ;
        RECT 29.560 18.755 117.600 18.925 ;
        RECT 29.560 18.275 117.600 18.445 ;
        RECT 29.560 17.795 117.600 17.965 ;
        RECT 29.560 17.315 117.600 17.485 ;
        RECT 29.560 16.835 117.600 17.005 ;
        RECT 29.560 16.355 117.600 16.525 ;
        RECT 29.560 15.875 117.600 16.045 ;
        RECT 29.560 15.395 117.600 15.565 ;
        RECT 29.560 14.915 117.600 15.085 ;
        RECT 29.560 14.435 117.600 14.605 ;
        RECT 29.560 13.955 117.600 14.125 ;
        RECT 117.815 14.040 117.985 19.800 ;
        RECT 118.325 13.555 118.495 20.285 ;
        RECT 28.665 13.385 118.495 13.555 ;
      LAYER met1 ;
        RECT 60.700 211.430 132.290 211.900 ;
        RECT 60.620 204.380 132.290 211.430 ;
        RECT 41.950 190.250 45.000 190.265 ;
        RECT 48.950 190.250 52.000 190.265 ;
        RECT 55.950 190.250 59.000 190.265 ;
        RECT 34.950 190.205 59.000 190.250 ;
        RECT 34.560 187.230 59.000 190.205 ;
        RECT 34.560 187.155 37.610 187.230 ;
        RECT 41.950 187.215 45.000 187.230 ;
        RECT 48.950 187.215 52.000 187.230 ;
        RECT 55.950 187.215 59.000 187.230 ;
        RECT 60.620 185.610 63.550 204.380 ;
        RECT 127.240 187.540 128.520 187.710 ;
        RECT 127.240 183.525 128.920 187.540 ;
        RECT 41.950 183.215 45.000 183.265 ;
        RECT 48.950 183.215 52.000 183.265 ;
        RECT 55.950 183.215 59.000 183.265 ;
        RECT 34.915 183.205 59.000 183.215 ;
        RECT 34.560 180.215 59.000 183.205 ;
        RECT 63.190 182.615 66.570 183.460 ;
        RECT 73.615 182.910 73.935 182.915 ;
        RECT 73.590 182.680 73.960 182.910 ;
        RECT 70.110 182.615 71.420 182.680 ;
        RECT 63.190 182.360 73.180 182.615 ;
        RECT 73.335 182.360 73.565 182.480 ;
        RECT 73.985 182.380 74.215 182.480 ;
        RECT 63.190 180.680 73.580 182.360 ;
        RECT 73.985 180.790 76.600 182.380 ;
        RECT 73.985 180.680 74.215 180.790 ;
        RECT 34.560 180.195 58.965 180.215 ;
        RECT 34.560 180.155 37.610 180.195 ;
        RECT 63.190 180.010 66.570 180.680 ;
        RECT 45.160 150.120 45.990 179.160 ;
        RECT 60.510 177.500 61.370 179.620 ;
        RECT 50.130 174.600 51.670 177.480 ;
        RECT 58.780 177.470 62.810 177.500 ;
        RECT 53.980 176.800 68.090 177.470 ;
        RECT 53.980 176.710 61.690 176.800 ;
        RECT 53.980 176.570 59.940 176.710 ;
        RECT 62.260 176.610 68.090 176.800 ;
        RECT 53.430 175.940 53.810 176.390 ;
        RECT 53.970 176.340 59.970 176.570 ;
        RECT 62.110 176.380 68.110 176.610 ;
        RECT 60.170 176.360 60.510 176.380 ;
        RECT 61.570 176.360 61.950 176.380 ;
        RECT 60.170 176.290 61.950 176.360 ;
        RECT 60.130 175.990 61.950 176.290 ;
        RECT 68.260 175.990 68.640 176.400 ;
        RECT 60.130 175.970 68.640 175.990 ;
        RECT 60.170 175.950 68.640 175.970 ;
        RECT 60.170 175.920 68.630 175.950 ;
        RECT 53.970 175.690 59.970 175.920 ;
        RECT 60.170 175.910 60.510 175.920 ;
        RECT 61.770 175.800 68.630 175.920 ;
        RECT 56.770 175.360 58.660 175.690 ;
        RECT 62.020 175.570 68.630 175.800 ;
        RECT 63.360 174.740 65.100 175.570 ;
        RECT 69.210 174.280 69.580 180.680 ;
        RECT 70.110 180.575 71.420 180.680 ;
        RECT 73.085 180.480 73.375 180.680 ;
        RECT 127.240 180.505 128.485 183.525 ;
        RECT 73.085 180.190 73.960 180.480 ;
        RECT 52.695 174.270 55.730 174.280 ;
        RECT 57.160 174.270 59.480 174.280 ;
        RECT 52.695 174.040 59.480 174.270 ;
        RECT 52.695 174.030 59.460 174.040 ;
        RECT 50.670 172.700 51.220 172.730 ;
        RECT 50.160 172.680 51.490 172.700 ;
        RECT 52.695 172.680 52.945 174.030 ;
        RECT 62.370 173.920 69.580 174.280 ;
        RECT 56.890 173.780 57.120 173.845 ;
        RECT 50.090 171.260 53.540 172.680 ;
        RECT 50.160 170.170 51.530 171.260 ;
        RECT 50.160 159.930 51.490 170.170 ;
        RECT 50.160 152.860 51.470 154.965 ;
        RECT 50.520 151.860 51.330 152.860 ;
        RECT 52.520 150.200 55.400 150.550 ;
        RECT 49.030 150.170 55.400 150.200 ;
        RECT 45.090 149.380 45.990 150.120 ;
        RECT 48.990 149.920 55.400 150.170 ;
        RECT 48.750 149.690 48.980 149.735 ;
        RECT 45.090 116.290 45.950 149.380 ;
        RECT 48.720 122.430 49.090 149.690 ;
        RECT 48.750 120.300 48.980 122.430 ;
        RECT 49.400 122.030 49.630 149.735 ;
        RECT 50.050 149.670 50.280 149.735 ;
        RECT 49.990 122.420 50.380 149.670 ;
        RECT 49.310 120.350 49.820 122.030 ;
        RECT 48.580 119.735 48.980 120.300 ;
        RECT 49.400 119.735 49.630 120.350 ;
        RECT 50.050 119.735 50.280 122.420 ;
        RECT 50.700 122.040 50.930 149.735 ;
        RECT 51.350 149.620 51.580 149.735 ;
        RECT 51.190 123.320 51.600 149.620 ;
        RECT 52.520 149.550 55.400 149.920 ;
        RECT 56.800 142.050 57.230 173.780 ;
        RECT 56.890 137.845 57.120 142.050 ;
        RECT 57.540 141.670 57.770 173.845 ;
        RECT 58.190 173.840 58.420 173.845 ;
        RECT 58.050 142.110 58.480 173.840 ;
        RECT 57.430 139.640 57.890 141.670 ;
        RECT 57.540 139.400 57.770 139.640 ;
        RECT 57.350 139.250 57.860 139.400 ;
        RECT 57.420 137.910 57.820 139.250 ;
        RECT 57.540 137.845 57.770 137.910 ;
        RECT 58.190 137.845 58.420 142.110 ;
        RECT 58.840 141.670 59.070 173.845 ;
        RECT 59.490 173.740 59.720 173.845 ;
        RECT 62.145 173.740 62.375 173.775 ;
        RECT 59.390 142.270 59.790 173.740 ;
        RECT 58.690 139.640 59.150 141.670 ;
        RECT 58.840 137.845 59.070 139.640 ;
        RECT 59.490 137.845 59.720 142.270 ;
        RECT 62.130 142.010 62.500 173.740 ;
        RECT 57.160 137.420 59.460 137.640 ;
        RECT 60.090 137.470 61.770 138.260 ;
        RECT 62.145 137.775 62.375 142.010 ;
        RECT 62.795 141.740 63.025 173.775 ;
        RECT 63.445 173.740 63.675 173.775 ;
        RECT 63.390 142.010 63.820 173.740 ;
        RECT 62.650 139.580 63.200 141.740 ;
        RECT 62.795 137.775 63.025 139.580 ;
        RECT 63.445 137.775 63.675 142.010 ;
        RECT 64.095 141.730 64.325 173.775 ;
        RECT 64.745 173.740 64.975 173.775 ;
        RECT 64.600 142.010 65.030 173.740 ;
        RECT 69.970 164.190 71.510 175.190 ;
        RECT 74.600 170.930 74.920 170.960 ;
        RECT 75.250 170.930 75.570 170.960 ;
        RECT 75.900 170.930 76.220 170.960 ;
        RECT 76.550 170.930 76.870 170.960 ;
        RECT 74.600 170.700 76.930 170.930 ;
        RECT 74.320 169.890 74.550 170.525 ;
        RECT 69.970 162.160 71.680 164.190 ;
        RECT 70.920 162.120 71.680 162.160 ;
        RECT 69.310 149.610 73.170 150.590 ;
        RECT 70.170 149.210 73.150 149.610 ;
        RECT 70.170 148.670 71.880 149.210 ;
        RECT 63.950 139.610 64.450 141.730 ;
        RECT 64.095 137.775 64.325 139.610 ;
        RECT 64.745 137.775 64.975 142.010 ;
        RECT 70.170 140.290 71.870 148.670 ;
        RECT 74.270 142.870 74.650 169.890 ;
        RECT 74.320 140.525 74.550 142.870 ;
        RECT 74.970 142.620 75.200 170.525 ;
        RECT 75.620 169.900 75.850 170.525 ;
        RECT 75.560 142.880 75.940 169.900 ;
        RECT 74.790 140.520 75.370 142.620 ;
        RECT 75.620 140.525 75.850 142.880 ;
        RECT 76.270 142.620 76.500 170.525 ;
        RECT 76.920 169.900 77.150 170.525 ;
        RECT 76.750 142.870 77.240 169.900 ;
        RECT 89.540 160.950 92.710 171.550 ;
        RECT 76.180 140.540 76.680 142.620 ;
        RECT 76.270 140.525 76.500 140.540 ;
        RECT 76.920 140.525 77.150 142.870 ;
        RECT 74.600 140.290 74.920 140.320 ;
        RECT 75.250 140.290 75.570 140.320 ;
        RECT 75.900 140.290 76.220 140.320 ;
        RECT 76.550 140.310 76.870 140.320 ;
        RECT 86.440 140.310 87.380 140.450 ;
        RECT 76.550 140.290 87.380 140.310 ;
        RECT 70.170 140.240 73.150 140.290 ;
        RECT 74.600 140.240 87.380 140.290 ;
        RECT 70.170 140.070 87.380 140.240 ;
        RECT 74.610 140.050 87.380 140.070 ;
        RECT 86.440 139.970 87.380 140.050 ;
        RECT 90.720 140.230 91.535 160.950 ;
        RECT 76.040 139.820 77.190 139.830 ;
        RECT 76.040 139.260 77.700 139.820 ;
        RECT 90.720 139.415 98.205 140.230 ;
        RECT 76.550 139.250 77.700 139.260 ;
        RECT 62.425 137.550 62.745 137.570 ;
        RECT 63.075 137.550 63.395 137.570 ;
        RECT 63.725 137.550 64.045 137.570 ;
        RECT 64.375 137.550 64.695 137.570 ;
        RECT 57.170 137.410 57.490 137.420 ;
        RECT 57.820 137.410 58.140 137.420 ;
        RECT 58.470 137.410 58.790 137.420 ;
        RECT 59.120 137.410 59.440 137.420 ;
        RECT 62.420 137.330 64.730 137.550 ;
        RECT 59.170 135.220 62.820 136.210 ;
        RECT 55.170 134.680 69.320 134.780 ;
        RECT 54.975 134.450 84.975 134.680 ;
        RECT 54.390 123.740 54.770 134.400 ;
        RECT 55.170 134.210 69.320 134.450 ;
        RECT 69.960 133.670 84.830 133.930 ;
        RECT 85.180 133.720 85.410 134.400 ;
        RECT 54.975 133.440 84.975 133.670 ;
        RECT 69.960 133.200 84.830 133.440 ;
        RECT 55.170 132.660 69.320 132.900 ;
        RECT 85.180 132.710 85.410 133.390 ;
        RECT 54.975 132.430 84.975 132.660 ;
        RECT 55.170 132.170 69.320 132.430 ;
        RECT 70.000 131.650 84.790 132.000 ;
        RECT 85.180 131.700 85.410 132.380 ;
        RECT 54.975 131.420 84.975 131.650 ;
        RECT 70.000 131.130 84.790 131.420 ;
        RECT 55.190 130.640 69.340 130.880 ;
        RECT 85.180 130.690 85.410 131.370 ;
        RECT 54.975 130.410 84.975 130.640 ;
        RECT 55.190 130.150 69.340 130.410 ;
        RECT 69.980 129.630 84.810 129.980 ;
        RECT 85.180 129.680 85.410 130.360 ;
        RECT 54.975 129.400 84.975 129.630 ;
        RECT 69.980 129.160 84.810 129.400 ;
        RECT 55.170 128.620 69.320 128.840 ;
        RECT 85.180 128.670 85.410 129.350 ;
        RECT 88.480 129.330 94.100 132.030 ;
        RECT 54.975 128.390 84.975 128.620 ;
        RECT 55.170 128.110 69.320 128.390 ;
        RECT 70.000 127.610 84.830 127.860 ;
        RECT 85.180 127.660 85.410 128.340 ;
        RECT 54.975 127.380 84.975 127.610 ;
        RECT 88.370 127.400 94.100 129.330 ;
        RECT 70.000 127.040 84.830 127.380 ;
        RECT 55.190 126.600 69.340 126.970 ;
        RECT 85.180 126.650 85.410 127.330 ;
        RECT 88.370 127.285 94.060 127.400 ;
        RECT 54.975 126.370 84.975 126.600 ;
        RECT 55.190 126.240 69.340 126.370 ;
        RECT 71.810 125.580 84.800 125.990 ;
        RECT 97.400 124.160 98.190 139.415 ;
        RECT 63.040 123.740 69.560 123.760 ;
        RECT 54.390 123.690 69.560 123.740 ;
        RECT 54.390 123.460 69.850 123.690 ;
        RECT 50.520 120.360 51.060 122.040 ;
        RECT 50.700 119.735 50.930 120.360 ;
        RECT 51.350 119.735 51.580 123.320 ;
        RECT 54.390 121.130 69.560 123.460 ;
        RECT 97.400 123.400 102.640 124.160 ;
        RECT 97.400 123.385 98.190 123.400 ;
        RECT 69.920 123.255 70.450 123.270 ;
        RECT 54.390 121.090 54.770 121.130 ;
        RECT 63.040 120.050 69.560 121.130 ;
        RECT 69.900 120.270 70.450 123.255 ;
        RECT 69.900 120.255 70.130 120.270 ;
        RECT 63.040 119.820 69.850 120.050 ;
        RECT 63.040 119.790 69.560 119.820 ;
        RECT 45.090 114.350 46.460 116.290 ;
        RECT 45.150 114.185 46.460 114.350 ;
        RECT 48.580 100.680 48.850 119.735 ;
        RECT 49.030 119.290 51.330 119.540 ;
        RECT 50.580 118.390 51.580 119.010 ;
        RECT 63.500 110.350 63.930 119.790 ;
        RECT 88.370 119.560 94.060 121.605 ;
        RECT 101.880 120.910 102.640 123.400 ;
        RECT 127.240 122.130 128.920 180.505 ;
        RECT 102.980 121.170 112.730 121.480 ;
        RECT 102.820 120.940 120.820 121.170 ;
        RECT 103.020 120.930 112.740 120.940 ;
        RECT 101.880 119.890 102.680 120.910 ;
        RECT 103.030 120.830 112.740 120.930 ;
        RECT 113.090 120.520 120.590 120.680 ;
        RECT 102.820 120.290 120.820 120.520 ;
        RECT 113.090 120.070 120.590 120.290 ;
        RECT 101.880 119.780 102.640 119.890 ;
        RECT 102.860 119.870 112.720 119.960 ;
        RECT 120.960 119.880 128.920 122.130 ;
        RECT 102.820 119.640 120.820 119.870 ;
        RECT 120.960 119.820 128.070 119.880 ;
        RECT 120.970 119.790 121.460 119.820 ;
        RECT 102.860 119.480 112.720 119.640 ;
        RECT 113.090 118.870 120.590 119.350 ;
        RECT 71.840 117.270 84.720 117.280 ;
        RECT 71.810 116.850 84.720 117.270 ;
        RECT 71.810 116.810 72.060 116.850 ;
        RECT 84.470 116.820 84.720 116.850 ;
        RECT 87.730 116.460 109.000 116.640 ;
        RECT 64.105 116.230 109.105 116.460 ;
        RECT 87.730 115.840 109.000 116.230 ;
        RECT 71.780 115.450 85.990 115.680 ;
        RECT 109.310 115.500 109.540 116.180 ;
        RECT 64.105 115.220 109.105 115.450 ;
        RECT 71.780 114.900 85.990 115.220 ;
        RECT 87.790 114.440 108.740 114.790 ;
        RECT 109.310 114.490 109.540 115.170 ;
        RECT 64.105 114.210 109.105 114.440 ;
        RECT 87.790 113.850 108.740 114.210 ;
        RECT 64.730 113.430 86.010 113.850 ;
        RECT 109.310 113.480 109.540 114.160 ;
        RECT 64.105 113.200 109.105 113.430 ;
        RECT 64.730 112.840 86.010 113.200 ;
        RECT 87.810 112.420 108.760 112.730 ;
        RECT 109.310 112.470 109.540 113.150 ;
        RECT 64.105 112.190 109.105 112.420 ;
        RECT 87.810 111.790 108.760 112.190 ;
        RECT 64.680 111.410 85.960 111.760 ;
        RECT 109.310 111.460 109.540 112.140 ;
        RECT 64.105 111.180 109.105 111.410 ;
        RECT 64.680 110.750 85.960 111.180 ;
        RECT 87.810 110.400 108.860 110.780 ;
        RECT 109.310 110.450 109.540 111.130 ;
        RECT 64.105 110.170 109.105 110.400 ;
        RECT 87.810 109.980 108.860 110.170 ;
        RECT 111.740 110.060 112.610 116.450 ;
        RECT 48.580 100.670 49.320 100.680 ;
        RECT 48.710 100.490 49.320 100.670 ;
        RECT 48.710 99.910 52.650 100.490 ;
        RECT 48.720 99.870 52.650 99.910 ;
        RECT 48.720 99.840 50.010 99.870 ;
        RECT 48.870 99.820 50.010 99.840 ;
        RECT 52.360 97.770 52.630 99.870 ;
        RECT 59.300 99.780 62.680 101.310 ;
        RECT 53.700 99.680 68.000 99.780 ;
        RECT 53.700 99.490 59.710 99.680 ;
        RECT 62.040 99.490 68.050 99.680 ;
        RECT 53.700 99.430 59.700 99.490 ;
        RECT 62.050 99.450 68.050 99.490 ;
        RECT 53.250 99.020 53.550 99.420 ;
        RECT 59.850 99.280 61.890 99.430 ;
        RECT 68.210 99.280 68.440 99.400 ;
        RECT 56.860 99.010 58.400 99.150 ;
        RECT 59.850 99.050 68.440 99.280 ;
        RECT 53.700 98.780 59.700 99.010 ;
        RECT 61.600 98.810 68.440 99.050 ;
        RECT 62.050 98.800 68.050 98.810 ;
        RECT 56.860 98.710 58.400 98.780 ;
        RECT 63.500 98.650 65.000 98.800 ;
        RECT 62.420 97.770 62.840 97.790 ;
        RECT 45.150 97.210 46.460 97.545 ;
        RECT 49.780 97.210 51.090 97.610 ;
        RECT 52.360 97.540 62.840 97.770 ;
        RECT 45.150 96.850 55.140 97.210 ;
        RECT 57.180 96.850 59.500 96.870 ;
        RECT 45.150 96.650 59.500 96.850 ;
        RECT 45.150 95.780 55.140 96.650 ;
        RECT 57.180 96.630 59.500 96.650 ;
        RECT 62.420 96.810 62.840 97.540 ;
        RECT 62.420 96.570 64.750 96.810 ;
        RECT 56.910 96.370 57.140 96.435 ;
        RECT 45.150 95.440 46.460 95.780 ;
        RECT 49.780 95.505 51.090 95.780 ;
        RECT 49.670 87.780 51.160 92.970 ;
        RECT 49.670 85.580 51.180 87.780 ;
        RECT 49.670 85.560 51.160 85.580 ;
        RECT 56.820 64.640 57.250 96.370 ;
        RECT 56.910 60.435 57.140 64.640 ;
        RECT 57.560 64.350 57.790 96.435 ;
        RECT 58.210 96.430 58.440 96.435 ;
        RECT 58.070 64.700 58.500 96.430 ;
        RECT 57.460 62.320 57.920 64.350 ;
        RECT 57.560 61.890 57.790 62.320 ;
        RECT 57.500 60.620 57.870 61.890 ;
        RECT 57.560 60.435 57.790 60.620 ;
        RECT 58.210 60.435 58.440 64.700 ;
        RECT 58.860 64.350 59.090 96.435 ;
        RECT 59.440 96.150 59.810 96.460 ;
        RECT 62.165 96.300 62.395 96.365 ;
        RECT 59.440 64.680 59.790 96.150 ;
        RECT 58.720 62.320 59.180 64.350 ;
        RECT 58.860 60.435 59.090 62.320 ;
        RECT 59.510 60.435 59.740 64.680 ;
        RECT 62.120 64.650 62.560 96.300 ;
        RECT 60.110 60.450 61.780 61.440 ;
        RECT 62.165 60.365 62.395 64.650 ;
        RECT 62.815 64.360 63.045 96.365 ;
        RECT 63.465 96.330 63.695 96.365 ;
        RECT 63.410 64.600 63.840 96.330 ;
        RECT 62.650 62.170 63.180 64.360 ;
        RECT 62.815 60.365 63.045 62.170 ;
        RECT 63.465 60.365 63.695 64.600 ;
        RECT 64.115 64.320 64.345 96.365 ;
        RECT 64.765 96.330 64.995 96.365 ;
        RECT 64.620 64.600 65.050 96.330 ;
        RECT 63.970 62.200 64.470 64.320 ;
        RECT 64.115 60.365 64.345 62.200 ;
        RECT 64.765 60.365 64.995 64.600 ;
        RECT 57.180 60.010 59.480 60.230 ;
        RECT 62.445 60.140 62.765 60.160 ;
        RECT 63.095 60.140 63.415 60.160 ;
        RECT 63.745 60.140 64.065 60.160 ;
        RECT 64.395 60.140 64.715 60.160 ;
        RECT 57.190 60.000 57.510 60.010 ;
        RECT 57.840 60.000 58.160 60.010 ;
        RECT 58.490 60.000 58.810 60.010 ;
        RECT 59.140 60.000 59.460 60.010 ;
        RECT 62.440 59.920 64.750 60.140 ;
        RECT 57.600 59.290 58.560 59.450 ;
        RECT 57.600 59.280 68.470 59.290 ;
        RECT 57.600 59.275 102.140 59.280 ;
        RECT 57.600 59.270 102.350 59.275 ;
        RECT 57.600 59.055 102.490 59.270 ;
        RECT 57.600 59.040 68.470 59.055 ;
        RECT 57.600 58.960 58.560 59.040 ;
        RECT 59.120 57.930 62.900 58.870 ;
        RECT 59.130 57.270 62.890 57.420 ;
        RECT 54.995 57.040 84.995 57.270 ;
        RECT 54.410 46.330 54.790 56.990 ;
        RECT 59.130 56.790 62.890 57.040 ;
        RECT 70.030 56.260 84.800 56.580 ;
        RECT 85.200 56.310 85.430 56.990 ;
        RECT 54.995 56.030 84.995 56.260 ;
        RECT 70.030 55.680 84.800 56.030 ;
        RECT 55.190 55.250 69.340 55.490 ;
        RECT 85.200 55.300 85.430 55.980 ;
        RECT 54.995 55.020 84.995 55.250 ;
        RECT 55.190 54.760 69.340 55.020 ;
        RECT 70.020 54.240 84.810 54.590 ;
        RECT 85.200 54.290 85.430 54.970 ;
        RECT 54.995 54.010 84.995 54.240 ;
        RECT 70.020 53.720 84.810 54.010 ;
        RECT 55.210 53.230 69.360 53.470 ;
        RECT 85.200 53.280 85.430 53.960 ;
        RECT 54.995 53.000 84.995 53.230 ;
        RECT 55.210 52.740 69.360 53.000 ;
        RECT 70.000 52.220 84.830 52.570 ;
        RECT 85.200 52.270 85.430 52.950 ;
        RECT 54.995 51.990 84.995 52.220 ;
        RECT 70.000 51.750 84.830 51.990 ;
        RECT 55.190 51.210 69.340 51.430 ;
        RECT 85.200 51.260 85.430 51.940 ;
        RECT 54.995 50.980 84.995 51.210 ;
        RECT 55.190 50.700 69.340 50.980 ;
        RECT 70.020 50.200 84.850 50.450 ;
        RECT 85.200 50.250 85.430 50.930 ;
        RECT 88.350 50.420 94.300 53.850 ;
        RECT 102.285 51.910 102.490 59.055 ;
        RECT 54.995 49.970 84.995 50.200 ;
        RECT 70.020 49.630 84.850 49.970 ;
        RECT 55.210 49.190 69.360 49.560 ;
        RECT 85.200 49.240 85.430 49.920 ;
        RECT 88.390 49.875 94.080 50.420 ;
        RECT 102.295 49.330 102.480 51.910 ;
        RECT 54.995 48.960 84.995 49.190 ;
        RECT 55.210 48.830 69.360 48.960 ;
        RECT 71.810 48.010 84.810 48.590 ;
        RECT 63.060 46.330 69.580 46.350 ;
        RECT 54.410 46.280 69.580 46.330 ;
        RECT 54.410 46.050 69.870 46.280 ;
        RECT 54.410 43.720 69.580 46.050 ;
        RECT 69.940 45.845 70.470 45.860 ;
        RECT 54.410 43.680 54.790 43.720 ;
        RECT 63.060 42.640 69.580 43.720 ;
        RECT 69.920 42.860 70.470 45.845 ;
        RECT 69.920 42.845 70.150 42.860 ;
        RECT 63.060 42.410 69.870 42.640 ;
        RECT 63.060 42.380 69.580 42.410 ;
        RECT 63.520 32.940 63.950 42.380 ;
        RECT 88.390 42.150 94.080 44.195 ;
        RECT 102.300 43.500 102.475 49.330 ;
        RECT 122.560 44.720 124.870 47.275 ;
        RECT 103.000 43.760 112.750 44.070 ;
        RECT 102.840 43.530 120.840 43.760 ;
        RECT 103.040 43.520 112.760 43.530 ;
        RECT 102.300 42.480 102.700 43.500 ;
        RECT 103.050 43.420 112.760 43.520 ;
        RECT 113.110 43.110 120.790 43.270 ;
        RECT 102.840 42.880 120.840 43.110 ;
        RECT 113.110 42.730 120.790 42.880 ;
        RECT 102.300 42.475 102.475 42.480 ;
        RECT 103.140 42.460 112.680 42.630 ;
        RECT 102.840 42.230 120.840 42.460 ;
        RECT 120.980 42.410 124.870 44.720 ;
        RECT 120.990 42.380 121.480 42.410 ;
        RECT 103.140 42.120 112.680 42.230 ;
        RECT 113.160 41.440 120.910 41.890 ;
        RECT 71.800 39.350 84.800 39.930 ;
        RECT 87.750 39.050 109.020 39.220 ;
        RECT 64.125 38.820 109.125 39.050 ;
        RECT 87.750 38.450 109.020 38.820 ;
        RECT 64.840 38.040 86.060 38.270 ;
        RECT 109.330 38.090 109.560 38.770 ;
        RECT 64.125 37.810 109.125 38.040 ;
        RECT 64.840 37.440 86.060 37.810 ;
        RECT 87.720 37.030 108.780 37.350 ;
        RECT 109.330 37.080 109.560 37.760 ;
        RECT 64.125 36.800 109.125 37.030 ;
        RECT 87.720 36.460 108.780 36.800 ;
        RECT 64.710 36.020 86.070 36.330 ;
        RECT 109.330 36.070 109.560 36.750 ;
        RECT 64.125 35.790 109.125 36.020 ;
        RECT 64.710 35.530 86.070 35.790 ;
        RECT 87.740 35.010 108.800 35.300 ;
        RECT 109.330 35.060 109.560 35.740 ;
        RECT 64.125 34.780 109.125 35.010 ;
        RECT 87.740 34.410 108.800 34.780 ;
        RECT 64.710 34.000 86.070 34.310 ;
        RECT 109.330 34.050 109.560 34.730 ;
        RECT 64.125 33.770 109.125 34.000 ;
        RECT 64.710 33.510 86.070 33.770 ;
        RECT 87.770 32.990 108.850 33.390 ;
        RECT 109.330 33.040 109.560 33.720 ;
        RECT 64.125 32.760 109.125 32.990 ;
        RECT 87.770 32.630 108.850 32.760 ;
        RECT 87.820 32.610 108.820 32.630 ;
        RECT 111.555 23.490 113.440 40.030 ;
        RECT 111.600 22.865 113.440 23.490 ;
        RECT 111.600 20.955 119.690 22.865 ;
        RECT 111.600 20.930 113.370 20.955 ;
        RECT 50.100 20.180 52.100 20.600 ;
        RECT 58.490 19.915 117.520 20.000 ;
        RECT 29.175 19.730 29.345 19.800 ;
        RECT 29.120 14.590 29.440 19.730 ;
        RECT 29.580 19.685 117.580 19.915 ;
        RECT 58.490 19.620 117.520 19.685 ;
        RECT 50.100 19.435 52.120 19.520 ;
        RECT 29.580 19.205 117.580 19.435 ;
        RECT 50.100 19.130 52.120 19.205 ;
        RECT 44.080 18.955 46.800 19.000 ;
        RECT 58.480 18.955 117.460 19.020 ;
        RECT 29.580 18.725 117.580 18.955 ;
        RECT 44.080 18.660 46.800 18.725 ;
        RECT 58.480 18.640 117.460 18.725 ;
        RECT 50.100 18.475 52.120 18.580 ;
        RECT 29.580 18.245 117.580 18.475 ;
        RECT 50.100 18.170 52.120 18.245 ;
        RECT 44.140 17.995 46.800 18.070 ;
        RECT 58.480 17.995 117.460 18.080 ;
        RECT 29.580 17.765 117.580 17.995 ;
        RECT 44.140 17.740 46.800 17.765 ;
        RECT 58.480 17.700 117.460 17.765 ;
        RECT 50.110 17.515 52.190 17.620 ;
        RECT 29.580 17.285 117.580 17.515 ;
        RECT 50.110 17.230 52.190 17.285 ;
        RECT 44.130 17.035 46.800 17.120 ;
        RECT 58.480 17.035 117.460 17.130 ;
        RECT 29.580 16.805 117.580 17.035 ;
        RECT 44.130 16.760 46.800 16.805 ;
        RECT 58.480 16.750 117.460 16.805 ;
        RECT 50.110 16.555 52.190 16.660 ;
        RECT 29.580 16.325 117.580 16.555 ;
        RECT 50.110 16.250 52.190 16.325 ;
        RECT 44.140 16.075 46.810 16.160 ;
        RECT 58.480 16.075 117.460 16.170 ;
        RECT 29.580 15.845 117.580 16.075 ;
        RECT 44.140 15.800 46.810 15.845 ;
        RECT 58.480 15.790 117.460 15.845 ;
        RECT 50.060 15.595 52.140 15.700 ;
        RECT 29.580 15.365 117.580 15.595 ;
        RECT 50.060 15.290 52.140 15.365 ;
        RECT 44.140 15.115 46.810 15.200 ;
        RECT 58.480 15.115 117.460 15.210 ;
        RECT 29.580 14.885 117.580 15.115 ;
        RECT 44.140 14.840 46.810 14.885 ;
        RECT 58.480 14.830 117.460 14.885 ;
        RECT 50.040 14.635 52.120 14.740 ;
        RECT 29.175 14.425 29.345 14.590 ;
        RECT 29.145 14.135 29.375 14.425 ;
        RECT 29.580 14.405 117.580 14.635 ;
        RECT 50.040 14.330 52.120 14.405 ;
        RECT 44.130 14.155 46.800 14.250 ;
        RECT 58.480 14.155 117.460 14.260 ;
        RECT 29.175 14.040 29.345 14.135 ;
        RECT 29.580 13.925 117.580 14.155 ;
        RECT 44.130 13.890 46.800 13.925 ;
        RECT 58.480 13.880 117.460 13.925 ;
        RECT 117.780 13.870 119.690 20.955 ;
      LAYER met2 ;
        RECT 129.670 204.390 132.190 211.810 ;
        RECT 45.320 180.265 48.755 190.295 ;
        RECT 60.700 185.520 63.460 191.930 ;
        RECT 50.610 177.480 51.360 183.050 ;
        RECT 74.920 180.770 76.610 182.400 ;
        RECT 50.130 174.600 51.670 177.480 ;
        RECT 56.770 174.560 58.510 175.860 ;
        RECT 63.370 174.790 65.100 175.940 ;
        RECT 63.360 174.740 65.100 174.790 ;
        RECT 56.780 173.750 58.490 174.560 ;
        RECT 56.780 171.490 59.790 173.750 ;
        RECT 63.360 173.740 65.080 174.740 ;
        RECT 54.770 168.340 59.790 171.490 ;
        RECT 50.510 153.370 51.320 153.960 ;
        RECT 48.765 151.860 51.320 153.370 ;
        RECT 48.765 151.845 50.400 151.860 ;
        RECT 48.765 149.740 50.290 151.845 ;
        RECT 48.710 149.630 50.390 149.740 ;
        RECT 48.710 123.320 51.600 149.630 ;
        RECT 52.520 149.550 55.400 150.550 ;
        RECT 56.780 142.270 59.790 168.340 ;
        RECT 56.780 142.050 58.490 142.270 ;
        RECT 62.150 142.010 65.080 173.740 ;
        RECT 74.250 169.910 75.920 169.920 ;
        RECT 74.250 164.195 77.250 169.910 ;
        RECT 89.560 168.300 92.700 171.490 ;
        RECT 70.915 162.120 77.250 164.195 ;
        RECT 69.310 149.610 73.170 150.590 ;
        RECT 74.250 142.880 77.250 162.120 ;
        RECT 74.250 142.870 75.920 142.880 ;
        RECT 74.860 142.580 76.730 142.620 ;
        RECT 63.360 141.990 65.080 142.010 ;
        RECT 57.430 141.680 64.450 141.730 ;
        RECT 57.420 139.640 64.450 141.680 ;
        RECT 57.930 139.350 59.170 139.390 ;
        RECT 57.380 138.190 59.170 139.350 ;
        RECT 57.380 137.930 59.100 138.190 ;
        RECT 57.420 137.910 57.820 137.930 ;
        RECT 52.470 135.470 54.750 136.660 ;
        RECT 59.840 136.240 62.100 139.640 ;
        RECT 62.680 139.590 64.450 139.640 ;
        RECT 74.520 140.520 76.730 142.580 ;
        RECT 74.520 137.100 76.720 140.520 ;
        RECT 86.440 139.970 87.380 140.450 ;
        RECT 86.570 138.150 87.370 139.970 ;
        RECT 48.710 122.410 50.390 123.320 ;
        RECT 49.300 122.000 51.060 122.040 ;
        RECT 49.300 120.360 51.580 122.000 ;
        RECT 50.570 116.420 51.580 120.360 ;
        RECT 52.510 116.420 53.580 135.470 ;
        RECT 59.100 134.790 62.870 136.240 ;
        RECT 73.640 135.630 76.720 137.100 ;
        RECT 73.640 135.500 76.440 135.630 ;
        RECT 55.160 133.420 69.320 134.790 ;
        RECT 55.190 132.900 69.320 133.420 ;
        RECT 55.170 132.620 69.320 132.900 ;
        RECT 55.160 126.700 69.320 132.620 ;
        RECT 55.160 126.410 69.300 126.700 ;
        RECT 69.980 126.440 84.840 134.590 ;
        RECT 55.170 126.280 69.300 126.410 ;
        RECT 54.360 121.110 58.240 123.410 ;
        RECT 71.790 123.290 84.800 126.440 ;
        RECT 69.960 120.240 84.800 123.290 ;
        RECT 86.600 121.700 87.370 138.150 ;
        RECT 88.610 129.940 94.020 132.050 ;
        RECT 92.655 121.860 103.075 121.865 ;
        RECT 86.600 121.575 91.100 121.700 ;
        RECT 92.655 121.575 112.730 121.860 ;
        RECT 86.600 120.720 112.730 121.575 ;
        RECT 127.470 121.330 128.220 187.610 ;
        RECT 71.790 118.340 84.800 120.240 ;
        RECT 86.650 119.480 112.730 120.720 ;
        RECT 113.090 120.620 120.590 120.680 ;
        RECT 113.090 119.550 120.610 120.620 ;
        RECT 71.810 116.480 84.720 118.340 ;
        RECT 88.360 118.240 94.000 119.480 ;
        RECT 113.070 118.870 120.610 119.550 ;
        RECT 130.090 118.870 131.950 120.670 ;
        RECT 88.365 116.640 94.000 118.240 ;
        RECT 113.060 118.780 131.950 118.870 ;
        RECT 113.060 117.970 131.930 118.780 ;
        RECT 50.270 116.380 65.590 116.420 ;
        RECT 71.790 116.380 84.800 116.480 ;
        RECT 87.730 116.450 109.000 116.640 ;
        RECT 87.730 116.420 109.030 116.450 ;
        RECT 50.270 110.110 86.020 116.380 ;
        RECT 87.730 115.840 112.460 116.420 ;
        RECT 87.740 110.120 112.460 115.840 ;
        RECT 64.780 110.090 86.020 110.110 ;
        RECT 59.330 100.360 62.620 101.270 ;
        RECT 56.900 98.895 58.390 99.150 ;
        RECT 56.900 98.010 58.395 98.895 ;
        RECT 56.800 96.420 58.510 98.010 ;
        RECT 63.510 97.890 65.000 99.130 ;
        RECT 59.440 96.420 59.810 96.460 ;
        RECT 56.800 96.170 59.810 96.420 ;
        RECT 63.380 96.300 65.100 97.890 ;
        RECT 44.120 85.190 51.380 87.880 ;
        RECT 44.135 13.350 46.800 85.190 ;
        RECT 56.800 65.330 59.780 96.170 ;
        RECT 54.370 65.310 59.780 65.330 ;
        RECT 53.870 64.650 59.780 65.310 ;
        RECT 53.870 64.640 58.510 64.650 ;
        RECT 53.870 64.630 58.220 64.640 ;
        RECT 62.140 64.630 65.100 96.300 ;
        RECT 53.870 64.610 57.720 64.630 ;
        RECT 53.870 59.375 54.570 64.610 ;
        RECT 63.380 64.580 65.100 64.630 ;
        RECT 57.450 64.290 59.190 64.360 ;
        RECT 62.700 64.290 64.470 64.320 ;
        RECT 57.420 62.180 64.470 64.290 ;
        RECT 60.100 61.920 61.780 62.180 ;
        RECT 57.480 60.610 61.780 61.920 ;
        RECT 57.600 59.375 58.560 59.450 ;
        RECT 53.870 59.140 58.560 59.375 ;
        RECT 54.065 59.065 58.560 59.140 ;
        RECT 57.600 58.960 58.560 59.065 ;
        RECT 60.100 58.930 61.780 60.610 ;
        RECT 59.140 58.000 62.890 58.930 ;
        RECT 59.120 55.490 62.890 58.000 ;
        RECT 55.190 55.210 69.340 55.490 ;
        RECT 55.180 49.290 69.340 55.210 ;
        RECT 55.180 49.000 69.320 49.290 ;
        RECT 70.000 49.030 84.860 57.180 ;
        RECT 88.350 50.420 94.300 53.850 ;
        RECT 88.780 50.380 93.990 50.420 ;
        RECT 55.190 48.870 69.320 49.000 ;
        RECT 71.810 45.880 84.820 49.030 ;
        RECT 58.960 45.690 63.650 45.770 ;
        RECT 54.380 43.930 63.650 45.690 ;
        RECT 54.380 43.860 63.640 43.930 ;
        RECT 69.980 42.830 84.820 45.880 ;
        RECT 122.560 44.965 124.870 47.275 ;
        RECT 92.675 44.450 103.095 44.455 ;
        RECT 92.675 44.165 112.750 44.450 ;
        RECT 71.810 41.330 84.820 42.830 ;
        RECT 71.530 39.160 84.820 41.330 ;
        RECT 88.380 42.070 112.750 44.165 ;
        RECT 88.380 40.830 94.020 42.070 ;
        RECT 113.120 42.050 120.780 43.260 ;
        RECT 113.120 41.930 120.900 42.050 ;
        RECT 113.120 40.860 132.080 41.930 ;
        RECT 88.385 39.220 94.020 40.830 ;
        RECT 71.530 39.150 84.830 39.160 ;
        RECT 49.950 38.850 66.970 39.060 ;
        RECT 71.530 38.850 85.210 39.150 ;
        RECT 87.750 39.070 109.020 39.220 ;
        RECT 87.500 39.010 112.210 39.070 ;
        RECT 87.500 39.000 113.220 39.010 ;
        RECT 49.950 32.830 86.040 38.850 ;
        RECT 64.800 32.680 86.040 32.830 ;
        RECT 87.500 32.720 113.290 39.000 ;
        RECT 87.500 32.710 112.480 32.720 ;
        RECT 87.500 32.700 112.210 32.710 ;
        RECT 50.100 20.180 52.100 20.600 ;
        RECT 50.100 19.130 52.120 19.520 ;
        RECT 58.480 19.250 117.530 20.100 ;
        RECT 151.150 19.250 156.510 19.280 ;
        RECT 50.100 18.170 52.120 18.580 ;
        RECT 50.110 17.230 52.190 17.620 ;
        RECT 50.110 16.250 52.190 16.660 ;
        RECT 50.060 15.290 52.140 15.700 ;
        RECT 50.040 14.330 52.120 14.740 ;
        RECT 58.480 13.890 156.510 19.250 ;
        RECT 58.480 13.870 114.720 13.890 ;
        RECT 147.670 6.100 156.510 13.890 ;
        RECT 147.640 1.720 156.550 6.100 ;
      LAYER met3 ;
        RECT 129.670 204.390 132.190 211.810 ;
        RECT 50.090 201.790 76.500 201.840 ;
        RECT 50.090 197.870 76.650 201.790 ;
        RECT 60.630 185.480 69.370 192.080 ;
        RECT 67.770 178.160 69.330 185.480 ;
        RECT 75.020 182.400 76.650 197.870 ;
        RECT 74.920 180.840 76.650 182.400 ;
        RECT 95.930 187.610 128.090 187.640 ;
        RECT 74.920 180.770 76.610 180.840 ;
        RECT 59.460 177.380 69.350 178.160 ;
        RECT 54.860 168.450 56.180 171.410 ;
        RECT 52.520 149.550 55.400 150.550 ;
        RECT 52.470 135.470 54.750 136.660 ;
        RECT 50.350 110.140 52.000 116.440 ;
        RECT 54.430 62.230 58.170 123.340 ;
        RECT 59.470 101.230 63.630 177.380 ;
        RECT 89.560 168.300 92.700 171.490 ;
        RECT 95.930 157.240 128.220 187.610 ;
        RECT 127.470 155.640 128.220 157.240 ;
        RECT 69.310 149.610 73.170 150.590 ;
        RECT 73.640 135.500 76.440 137.100 ;
        RECT 88.910 130.180 93.870 131.850 ;
        RECT 95.930 125.240 128.220 155.640 ;
        RECT 127.470 121.330 128.220 125.240 ;
        RECT 120.730 120.220 131.990 120.610 ;
        RECT 120.690 119.670 131.990 120.220 ;
        RECT 110.140 110.200 111.630 116.360 ;
        RECT 112.100 101.690 132.260 117.090 ;
        RECT 59.410 100.470 63.630 101.230 ;
        RECT 59.410 100.390 62.530 100.470 ;
        RECT 67.960 63.430 98.360 95.590 ;
        RECT 99.960 63.430 130.360 95.590 ;
        RECT 54.430 62.220 57.420 62.230 ;
        RECT 54.430 60.430 57.310 62.220 ;
        RECT 54.430 59.925 57.420 60.430 ;
        RECT 51.185 58.535 57.420 59.925 ;
        RECT 51.185 48.000 52.575 58.535 ;
        RECT 54.430 58.130 57.420 58.535 ;
        RECT 88.350 50.420 94.300 53.850 ;
        RECT 88.780 50.380 93.990 50.420 ;
        RECT 51.185 47.535 58.170 48.000 ;
        RECT 51.195 45.690 58.170 47.535 ;
        RECT 58.960 45.690 63.650 45.770 ;
        RECT 51.195 45.445 63.650 45.690 ;
        RECT 51.910 44.260 63.650 45.445 ;
        RECT 122.560 44.965 124.870 47.275 ;
        RECT 54.380 43.930 63.650 44.260 ;
        RECT 54.380 43.860 63.640 43.930 ;
        RECT 54.430 40.710 58.170 43.860 ;
        RECT 130.120 40.890 132.030 41.910 ;
        RECT 50.230 33.010 51.820 38.920 ;
        RECT 50.100 20.180 52.100 20.600 ;
        RECT 50.100 19.130 52.120 19.520 ;
        RECT 50.100 18.170 52.120 18.580 ;
        RECT 50.110 17.230 52.190 17.620 ;
        RECT 50.110 16.250 52.190 16.660 ;
        RECT 50.060 15.290 52.140 15.700 ;
        RECT 50.040 14.330 52.120 14.740 ;
        RECT 54.460 7.090 57.850 40.710 ;
        RECT 112.800 39.000 132.960 39.100 ;
        RECT 112.300 32.720 132.960 39.000 ;
        RECT 112.800 23.700 132.960 32.720 ;
        RECT 54.340 5.080 134.590 7.090 ;
        RECT 54.340 4.500 134.630 5.080 ;
        RECT 54.340 3.800 136.190 4.500 ;
        RECT 129.670 3.330 136.190 3.800 ;
        RECT 129.580 3.100 136.190 3.330 ;
        RECT 129.580 1.350 136.140 3.100 ;
        RECT 147.640 1.720 156.550 6.100 ;
      LAYER met4 ;
        RECT 129.610 204.340 134.120 212.200 ;
        RECT 110.870 187.245 111.390 188.440 ;
        RECT 54.760 171.500 69.260 171.530 ;
        RECT 54.760 171.490 81.110 171.500 ;
        RECT 54.760 170.740 92.690 171.490 ;
        RECT 54.760 170.010 74.970 170.740 ;
        RECT 75.440 170.010 92.690 170.740 ;
        RECT 54.760 168.340 92.690 170.010 ;
        RECT 67.910 168.310 92.690 168.340 ;
        RECT 79.490 168.300 92.690 168.310 ;
        RECT 96.325 157.635 125.935 187.245 ;
        RECT 110.870 155.245 111.390 157.635 ;
        RECT 52.520 149.540 73.220 150.690 ;
        RECT 73.640 136.660 76.440 137.100 ;
        RECT 52.470 135.500 76.440 136.660 ;
        RECT 52.470 135.470 54.750 135.500 ;
        RECT 89.950 131.550 91.510 131.580 ;
        RECT 91.810 131.550 92.900 131.580 ;
        RECT 89.950 130.460 92.910 131.550 ;
        RECT 89.980 130.440 92.910 130.460 ;
        RECT 90.990 124.090 91.510 130.440 ;
        RECT 96.325 125.635 125.935 155.245 ;
        RECT 110.870 124.090 111.390 125.635 ;
        RECT 127.570 124.440 128.090 188.440 ;
        RECT 90.990 123.570 111.390 124.090 ;
        RECT 130.040 119.540 134.120 120.970 ;
        RECT 112.120 116.380 112.600 117.030 ;
        RECT 110.130 110.060 112.600 116.380 ;
        RECT 112.120 101.750 112.600 110.060 ;
        RECT 114.255 109.930 131.865 116.695 ;
        RECT 114.255 109.540 134.120 109.930 ;
        RECT 114.255 102.085 131.865 109.540 ;
        RECT 68.355 80.650 97.965 95.195 ;
        RECT 100.355 80.650 129.965 95.195 ;
        RECT 66.250 80.130 131.160 80.650 ;
        RECT 66.250 62.205 66.770 80.130 ;
        RECT 68.355 65.585 97.965 80.130 ;
        RECT 100.355 65.585 129.965 80.130 ;
        RECT 67.160 63.430 131.160 63.950 ;
        RECT 88.780 62.205 93.990 62.310 ;
        RECT 66.250 61.695 93.990 62.205 ;
        RECT 66.250 61.690 66.770 61.695 ;
        RECT 88.780 53.850 93.990 61.695 ;
        RECT 88.350 50.420 94.300 53.850 ;
        RECT 122.550 44.950 124.880 63.430 ;
        RECT 130.080 40.740 134.120 42.170 ;
        RECT 112.820 23.760 113.300 39.040 ;
        RECT 114.955 31.530 132.565 38.705 ;
        RECT 114.955 31.010 134.120 31.530 ;
        RECT 114.955 24.095 132.565 31.010 ;
        RECT 129.540 1.260 136.140 3.930 ;
        RECT 147.640 1.720 156.550 6.100 ;
        RECT 150.510 1.700 153.940 1.720 ;
        RECT 132.010 1.210 134.650 1.260 ;
        RECT 132.470 1.000 133.410 1.210 ;
        RECT 132.470 0.960 132.490 1.000 ;
        RECT 133.390 0.960 133.410 1.000 ;
        RECT 151.800 1.000 152.710 1.700 ;
        RECT 151.800 0.940 151.810 1.000 ;
  END
END tt_um_c0d3d1_ldo
END LIBRARY

